VERSION 5.7 ;
  NOWIREEXTENSIONATPIN ON ;
  DIVIDERCHAR "/" ;
  BUSBITCHARS "[]" ;
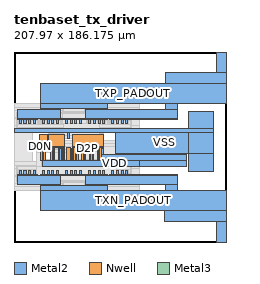
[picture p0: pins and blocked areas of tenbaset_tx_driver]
MACRO tenbaset_tx_driver
  CLASS BLOCK ;
  FOREIGN tenbaset_tx_driver ;
  ORIGIN 0.000 0.000 ;
  SIZE 207.970 BY 186.175 ;
  PIN VSS
    USE GROUND ;
    PORT
      LAYER Metal2 ;
        RECT 170.640 111.690 195.640 128.095 ;
        RECT 0.000 107.460 195.640 111.690 ;
        RECT 52.120 101.325 54.100 107.460 ;
        RECT 99.055 86.690 195.640 107.460 ;
        RECT 170.640 69.305 195.640 86.690 ;
        RECT 170.640 69.305 195.640 128.095 ;
    END
  END VSS
  PIN VDD
    USE POWER ;
    PORT
      LAYER Nwell ;
        RECT 24.710 92.110 32.350 104.990 ;
        RECT 34.050 92.110 49.330 104.990 ;
        RECT 26.450 79.410 30.610 92.110 ;
        RECT 35.790 79.410 39.950 92.110 ;
        RECT 43.430 79.410 47.590 92.110 ;
        RECT 51.030 79.410 55.190 92.290 ;
        RECT 56.890 92.110 87.450 104.990 ;
        RECT 58.630 79.410 62.790 92.110 ;
        RECT 66.270 79.410 70.430 92.110 ;
        RECT 73.910 79.410 78.070 92.110 ;
        RECT 81.550 79.410 85.710 92.110 ;
      LAYER Metal2 ;
        RECT 27.980 79.870 29.080 91.490 ;
        RECT 37.320 79.870 38.420 91.490 ;
        RECT 44.960 79.870 46.060 91.490 ;
        RECT 48.430 79.870 49.860 91.695 ;
        RECT 56.350 79.870 57.780 91.695 ;
        RECT 60.160 79.870 61.260 91.490 ;
        RECT 67.800 79.870 68.900 91.490 ;
        RECT 75.440 79.870 76.540 91.490 ;
        RECT 83.080 79.870 84.180 91.490 ;
        RECT 85.860 86.225 87.290 91.395 ;
        RECT 85.860 79.870 168.970 86.225 ;
        RECT 27.980 74.125 168.970 79.870 ;
        RECT 123.24 74.125 168.970 86.225 ;
    END
  END VDD
  PIN TXP_PADOUT
    ANTENNADIFFAREA 148.000000 ;
    PORT
      LAYER Metal2 ;
        RECT 197.970 165.675 207.970 186.175 ;
        RECT 147.970 155.675 207.970 165.675 ;
        RECT 25.940 135.675 207.970 155.675 ;
        RECT 25.940 130.975 91.300 135.675 ;
        RECT 25.940 130.280 45.960 130.975 ;
        RECT 3.270 121.280 45.960 130.280 ;
        RECT 70.370 130.280 91.300 130.975 ;
        RECT 147.970 130.280 160.685 135.675 ;
        RECT 70.370 121.280 160.685 130.280 ;
        RECT 3.270 119.750 23.290 121.280 ;
        RECT 25.940 119.750 91.300 121.280 ;
        RECT 93.950 119.750 160.685 121.280 ;
        RECT 5.180 115.710 7.180 119.750 ;
        RECT 9.780 115.710 11.780 119.750 ;
        RECT 14.385 115.710 16.385 119.750 ;
        RECT 18.990 115.710 20.990 119.750 ;
        RECT 27.850 115.710 29.850 119.750 ;
        RECT 32.450 115.710 34.450 119.750 ;
        RECT 37.055 115.710 39.055 119.750 ;
        RECT 41.660 115.710 43.660 119.750 ;
        RECT 50.520 115.710 52.520 119.750 ;
        RECT 55.120 115.710 57.120 119.750 ;
        RECT 59.725 115.710 61.725 119.750 ;
        RECT 64.330 115.710 66.330 119.750 ;
        RECT 73.190 115.710 75.190 119.750 ;
        RECT 77.790 115.710 79.790 119.750 ;
        RECT 82.395 115.710 84.395 119.750 ;
        RECT 87.000 115.710 89.000 119.750 ;
        RECT 95.860 115.710 97.860 119.750 ;
        RECT 100.460 115.710 102.460 119.750 ;
        RECT 105.065 115.710 107.065 119.750 ;
        RECT 109.670 115.710 111.670 119.750 ;
    END
  END TXP_PADOUT
  PIN TXN_PADOUT
    ANTENNADIFFAREA 148.000000 ;
    PORT
      LAYER Metal2 ;
        RECT 5.180 66.425 7.180 70.465 ;
        RECT 9.780 66.425 11.780 70.465 ;
        RECT 14.385 66.425 16.385 70.465 ;
        RECT 18.990 66.425 20.990 70.465 ;
        RECT 27.850 66.425 29.850 70.465 ;
        RECT 32.450 66.425 34.450 70.465 ;
        RECT 37.055 66.425 39.055 70.465 ;
        RECT 41.660 66.425 43.660 70.465 ;
        RECT 50.520 66.425 52.520 70.465 ;
        RECT 55.120 66.425 57.120 70.465 ;
        RECT 59.725 66.425 61.725 70.465 ;
        RECT 64.330 66.425 66.330 70.465 ;
        RECT 73.190 66.425 75.190 70.465 ;
        RECT 77.790 66.425 79.790 70.465 ;
        RECT 82.395 66.425 84.395 70.465 ;
        RECT 87.000 66.425 89.000 70.465 ;
        RECT 95.860 66.425 97.860 70.465 ;
        RECT 100.460 66.425 102.460 70.465 ;
        RECT 105.065 66.425 107.065 70.465 ;
        RECT 109.670 66.425 111.670 70.465 ;
        RECT 3.270 64.895 23.290 66.425 ;
        RECT 25.940 64.895 91.300 66.425 ;
        RECT 93.950 64.895 160.685 66.425 ;
        RECT 3.270 55.895 45.960 64.895 ;
        RECT 25.940 55.200 45.960 55.895 ;
        RECT 70.370 55.895 160.685 64.895 ;
        RECT 70.370 55.200 91.300 55.895 ;
        RECT 25.940 50.500 91.300 55.200 ;
        RECT 147.970 50.500 160.685 55.895 ;
        RECT 25.940 30.500 207.970 50.500 ;
        RECT 147.910 20.500 207.970 30.500 ;
        RECT 197.970 0.000 207.970 20.500 ;
    END
  END TXN_PADOUT
  PIN D0N
    ANTENNAGATEAREA 10.000000 ;
    PORT
      LAYER Metal2 ;
        RECT 25.460 92.930 25.960 93.250 ;
    END
  END D0N
  PIN D0P
    ANTENNAGATEAREA 10.000000 ;
    PORT
      LAYER Metal2 ;
        RECT 31.100 92.930 31.600 93.250 ;
    END
  END D0P
  PIN D1P
    ANTENNAGATEAREA 20.000000 ;
    PORT
      LAYER Metal2 ;
        RECT 40.440 92.930 42.940 93.250 ;
    END
  END D1P
  PIN D1N
    ANTENNAGATEAREA 20.000000 ;
    PORT
      LAYER Metal3 ;
        RECT 34.800 92.930 48.580 93.250 ;
    END
  END D1N
  PIN D2N
    ANTENNAGATEAREA 40.000000 ;
    PORT
      LAYER Metal3 ;
        RECT 57.640 92.930 86.700 93.250 ;
    END
  END D2N
  PIN D2P
    ANTENNAGATEAREA 40.000000 ;
    PORT
      LAYER Metal3 ;
        RECT 64.365 91.745 79.975 92.195 ;
    END
  END D2P
  OBS
      LAYER Metal1 ;
        RECT 0.000 131.565 123.240 135.565 ;
        RECT 0.000 129.145 47.340 131.565 ;
        RECT 48.605 129.405 68.630 130.675 ;
        RECT 69.900 129.145 123.240 131.565 ;
        RECT 0.000 128.785 123.240 129.145 ;
        RECT 0.000 122.105 47.700 128.785 ;
        RECT 48.610 128.055 68.630 128.435 ;
        RECT 48.000 127.315 48.380 127.985 ;
        RECT 48.000 126.935 68.630 127.315 ;
        RECT 48.000 125.075 48.380 126.935 ;
        RECT 48.610 125.815 68.630 126.195 ;
        RECT 48.000 124.695 68.630 125.075 ;
        RECT 48.000 122.905 48.380 124.695 ;
        RECT 48.610 123.575 68.630 123.955 ;
        RECT 48.000 122.835 48.610 122.905 ;
        RECT 48.000 122.455 68.630 122.835 ;
        RECT 69.540 122.105 123.240 128.785 ;
        RECT 0.000 120.920 123.240 122.105 ;
        RECT 0.000 114.240 2.360 120.920 ;
        RECT 3.270 120.190 23.290 120.570 ;
        RECT 2.660 115.040 3.040 120.120 ;
        RECT 3.270 119.070 23.290 119.450 ;
        RECT 3.270 117.950 23.290 118.330 ;
        RECT 3.270 116.830 23.290 117.210 ;
        RECT 3.270 115.710 23.290 116.090 ;
        RECT 3.270 114.590 23.290 114.970 ;
        RECT 24.200 114.240 25.030 120.920 ;
        RECT 25.940 120.190 45.960 120.570 ;
        RECT 25.330 115.040 25.710 120.120 ;
        RECT 25.940 119.070 45.960 119.450 ;
        RECT 25.940 117.950 45.960 118.330 ;
        RECT 25.940 116.830 45.960 117.210 ;
        RECT 25.940 115.710 45.960 116.090 ;
        RECT 25.940 114.590 45.960 114.970 ;
        RECT 46.870 114.240 47.700 120.920 ;
        RECT 48.610 120.190 68.630 120.570 ;
        RECT 48.000 115.040 48.380 120.120 ;
        RECT 48.610 119.070 68.630 119.450 ;
        RECT 48.610 117.950 68.630 118.330 ;
        RECT 48.610 116.830 68.630 117.210 ;
        RECT 48.610 115.710 68.630 116.090 ;
        RECT 48.610 114.590 68.630 114.970 ;
        RECT 69.540 114.240 70.370 120.920 ;
        RECT 71.280 120.190 91.300 120.570 ;
        RECT 70.670 115.040 71.050 120.120 ;
        RECT 71.280 119.070 91.300 119.450 ;
        RECT 71.280 117.950 91.300 118.330 ;
        RECT 71.280 116.830 91.300 117.210 ;
        RECT 71.280 115.710 91.300 116.090 ;
        RECT 71.280 114.590 91.300 114.970 ;
        RECT 92.210 114.240 93.040 120.920 ;
        RECT 93.950 120.190 113.970 120.570 ;
        RECT 93.340 115.040 93.720 120.120 ;
        RECT 93.950 119.070 113.970 119.450 ;
        RECT 93.950 117.950 113.970 118.330 ;
        RECT 93.950 116.830 113.970 117.210 ;
        RECT 93.950 115.710 113.970 116.090 ;
        RECT 93.950 114.590 113.970 114.970 ;
        RECT 114.880 114.240 123.240 120.920 ;
        RECT 0.000 113.880 123.240 114.240 ;
        RECT 0.000 111.690 2.000 113.880 ;
        RECT 3.265 112.350 23.290 113.620 ;
        RECT 24.200 111.690 25.030 113.880 ;
        RECT 25.935 112.350 45.960 113.620 ;
        RECT 46.870 111.690 47.700 113.880 ;
        RECT 48.605 112.350 68.630 113.620 ;
        RECT 69.540 111.690 70.370 113.880 ;
        RECT 71.275 112.350 91.300 113.620 ;
        RECT 92.210 111.690 93.040 113.880 ;
        RECT 93.945 112.350 113.970 113.620 ;
        RECT 115.240 111.690 123.240 113.880 ;
        RECT 0.000 107.460 123.240 111.690 ;
        RECT 0.000 78.715 18.355 107.460 ;
        RECT 24.870 104.470 49.170 104.830 ;
        RECT 24.870 92.630 25.230 104.470 ;
        RECT 25.580 93.540 25.960 103.560 ;
        RECT 26.600 93.540 26.980 103.560 ;
        RECT 27.620 93.540 28.000 103.560 ;
        RECT 25.460 92.930 27.550 93.250 ;
        RECT 28.350 92.630 28.710 104.470 ;
        RECT 29.060 93.540 29.440 103.560 ;
        RECT 30.080 93.540 30.460 103.560 ;
        RECT 31.100 93.540 31.480 103.560 ;
        RECT 29.510 92.930 31.600 93.250 ;
        RECT 31.830 92.630 34.570 104.470 ;
        RECT 34.920 93.540 35.300 103.560 ;
        RECT 35.940 93.540 36.320 103.560 ;
        RECT 36.960 93.540 37.340 103.560 ;
        RECT 34.800 92.930 36.890 93.250 ;
        RECT 37.690 92.630 38.050 104.470 ;
        RECT 38.400 93.540 38.780 103.560 ;
        RECT 39.420 93.540 39.800 103.560 ;
        RECT 40.440 93.540 40.820 103.560 ;
        RECT 38.850 92.930 40.940 93.250 ;
        RECT 41.170 92.630 42.210 104.470 ;
        RECT 42.560 93.540 42.940 103.560 ;
        RECT 43.580 93.540 43.960 103.560 ;
        RECT 44.600 93.540 44.980 103.560 ;
        RECT 42.440 92.930 44.530 93.250 ;
        RECT 45.330 92.630 45.690 104.470 ;
        RECT 46.040 93.540 46.420 103.560 ;
        RECT 47.060 93.540 47.440 103.560 ;
        RECT 48.080 93.540 48.460 103.560 ;
        RECT 46.490 92.930 48.580 93.250 ;
        RECT 48.810 92.630 49.170 104.470 ;
        RECT 52.110 104.295 54.070 107.460 ;
        RECT 57.050 104.470 87.290 104.830 ;
        RECT 52.110 103.935 54.110 104.295 ;
        RECT 52.110 103.065 54.100 103.935 ;
        RECT 52.120 101.325 54.100 103.065 ;
        RECT 24.870 92.270 49.170 92.630 ;
        RECT 52.120 92.360 54.100 94.405 ;
        RECT 57.050 92.630 57.410 104.470 ;
        RECT 57.760 93.540 58.140 103.560 ;
        RECT 58.780 93.540 59.160 103.560 ;
        RECT 59.800 93.540 60.180 103.560 ;
        RECT 57.640 92.930 59.730 93.250 ;
        RECT 60.530 92.630 60.890 104.470 ;
        RECT 61.240 93.540 61.620 103.560 ;
        RECT 62.260 93.540 62.640 103.560 ;
        RECT 63.280 93.540 63.660 103.560 ;
        RECT 61.690 92.930 63.780 93.250 ;
        RECT 64.010 92.630 65.050 104.470 ;
        RECT 65.400 93.540 65.780 103.560 ;
        RECT 66.420 93.540 66.800 103.560 ;
        RECT 67.440 93.540 67.820 103.560 ;
        RECT 65.280 92.930 67.370 93.250 ;
        RECT 68.170 92.630 68.530 104.470 ;
        RECT 68.880 93.540 69.260 103.560 ;
        RECT 69.900 93.540 70.280 103.560 ;
        RECT 70.920 93.540 71.300 103.560 ;
        RECT 69.330 92.930 71.420 93.250 ;
        RECT 71.650 92.630 72.690 104.470 ;
        RECT 73.040 93.540 73.420 103.560 ;
        RECT 74.060 93.540 74.440 103.560 ;
        RECT 75.080 93.540 75.460 103.560 ;
        RECT 72.920 92.930 75.010 93.250 ;
        RECT 75.810 92.630 76.170 104.470 ;
        RECT 76.520 93.540 76.900 103.560 ;
        RECT 77.540 93.540 77.920 103.560 ;
        RECT 78.560 93.540 78.940 103.560 ;
        RECT 76.970 92.930 79.060 93.250 ;
        RECT 79.290 92.630 80.330 104.470 ;
        RECT 80.680 93.540 81.060 103.560 ;
        RECT 81.700 93.540 82.080 103.560 ;
        RECT 82.720 93.540 83.100 103.560 ;
        RECT 80.560 92.930 82.650 93.250 ;
        RECT 83.450 92.630 83.810 104.470 ;
        RECT 84.160 93.540 84.540 103.560 ;
        RECT 85.180 93.540 85.560 103.560 ;
        RECT 86.200 93.540 86.580 103.560 ;
        RECT 84.610 92.930 86.700 93.250 ;
        RECT 86.930 92.630 87.290 104.470 ;
        RECT 57.050 92.270 87.290 92.630 ;
        RECT 26.610 91.090 30.450 92.270 ;
        RECT 26.610 79.930 26.970 91.090 ;
        RECT 27.320 80.840 27.700 90.860 ;
        RECT 28.340 80.840 28.720 91.090 ;
        RECT 29.360 80.840 29.740 90.860 ;
        RECT 27.200 80.230 29.290 80.590 ;
        RECT 30.090 79.930 30.450 91.090 ;
        RECT 26.610 79.570 30.450 79.930 ;
        RECT 35.950 92.130 51.190 92.270 ;
        RECT 55.030 92.130 87.290 92.270 ;
        RECT 35.950 91.770 87.290 92.130 ;
        RECT 35.950 91.090 51.550 91.770 ;
        RECT 35.950 79.930 36.310 91.090 ;
        RECT 36.660 80.840 37.040 90.860 ;
        RECT 37.680 80.840 38.060 91.090 ;
        RECT 38.700 80.840 39.080 90.860 ;
        RECT 36.540 80.230 38.630 80.590 ;
        RECT 39.430 79.930 39.790 91.090 ;
        RECT 35.950 79.570 39.790 79.930 ;
        RECT 43.590 79.930 43.950 91.090 ;
        RECT 44.300 80.840 44.680 90.860 ;
        RECT 45.320 80.840 45.700 91.090 ;
        RECT 47.070 90.860 51.550 91.090 ;
        RECT 46.340 80.840 46.720 90.860 ;
        RECT 47.070 80.840 52.280 90.860 ;
        RECT 44.750 80.230 46.840 80.590 ;
        RECT 47.070 79.930 51.550 80.840 ;
        RECT 52.540 80.550 53.680 91.470 ;
        RECT 54.670 91.090 87.290 91.770 ;
        RECT 54.670 90.860 59.150 91.090 ;
        RECT 53.940 80.840 59.150 90.860 ;
        RECT 59.500 80.840 59.880 90.860 ;
        RECT 60.520 80.840 60.900 91.090 ;
        RECT 61.540 80.840 61.920 90.860 ;
        RECT 52.350 80.230 53.870 80.550 ;
        RECT 54.670 79.930 59.150 80.840 ;
        RECT 59.380 80.230 61.470 80.590 ;
        RECT 62.270 79.930 62.630 91.090 ;
        RECT 43.590 79.570 62.630 79.930 ;
        RECT 66.430 79.930 66.790 91.090 ;
        RECT 67.140 80.840 67.520 90.860 ;
        RECT 68.160 80.840 68.540 91.090 ;
        RECT 69.180 80.840 69.560 90.860 ;
        RECT 67.590 80.230 69.680 80.590 ;
        RECT 69.910 79.930 70.270 91.090 ;
        RECT 66.430 79.570 70.270 79.930 ;
        RECT 74.070 79.930 74.430 91.090 ;
        RECT 74.780 80.840 75.160 90.860 ;
        RECT 75.800 80.840 76.180 91.090 ;
        RECT 76.820 80.840 77.200 90.860 ;
        RECT 74.660 80.230 76.750 80.590 ;
        RECT 77.550 79.930 77.910 91.090 ;
        RECT 74.070 79.570 77.910 79.930 ;
        RECT 81.710 79.930 82.070 91.090 ;
        RECT 82.420 80.840 82.800 90.860 ;
        RECT 83.440 80.840 83.820 91.090 ;
        RECT 84.460 80.840 84.840 90.860 ;
        RECT 82.870 80.230 84.960 80.590 ;
        RECT 85.190 79.930 87.290 91.090 ;
        RECT 81.710 79.570 87.290 79.930 ;
        RECT 99.055 78.715 123.240 107.460 ;
        RECT 0.000 74.485 123.240 78.715 ;
        RECT 0.000 72.295 2.000 74.485 ;
        RECT 3.265 72.555 23.290 73.825 ;
        RECT 24.200 72.295 25.030 74.485 ;
        RECT 25.935 72.555 45.960 73.825 ;
        RECT 46.870 72.295 47.700 74.485 ;
        RECT 48.605 72.555 68.630 73.825 ;
        RECT 69.540 72.295 70.370 74.485 ;
        RECT 71.275 72.555 91.300 73.825 ;
        RECT 92.210 72.295 93.040 74.485 ;
        RECT 93.945 72.555 113.970 73.825 ;
        RECT 115.240 72.295 123.240 74.485 ;
        RECT 0.000 71.935 123.240 72.295 ;
        RECT 0.000 65.255 2.360 71.935 ;
        RECT 3.270 71.205 23.290 71.585 ;
        RECT 2.660 66.055 3.040 71.135 ;
        RECT 3.270 70.085 23.290 70.465 ;
        RECT 3.270 68.965 23.290 69.345 ;
        RECT 3.270 67.845 23.290 68.225 ;
        RECT 3.270 66.725 23.290 67.105 ;
        RECT 3.270 65.605 23.290 65.985 ;
        RECT 24.200 65.255 25.030 71.935 ;
        RECT 25.940 71.205 45.960 71.585 ;
        RECT 25.330 66.055 25.710 71.135 ;
        RECT 25.940 70.085 45.960 70.465 ;
        RECT 25.940 68.965 45.960 69.345 ;
        RECT 25.940 67.845 45.960 68.225 ;
        RECT 25.940 66.725 45.960 67.105 ;
        RECT 25.940 65.605 45.960 65.985 ;
        RECT 46.870 65.255 47.700 71.935 ;
        RECT 48.610 71.205 68.630 71.585 ;
        RECT 48.000 66.055 48.380 71.135 ;
        RECT 48.610 70.085 68.630 70.465 ;
        RECT 48.610 68.965 68.630 69.345 ;
        RECT 48.610 67.845 68.630 68.225 ;
        RECT 48.610 66.725 68.630 67.105 ;
        RECT 48.610 65.605 68.630 65.985 ;
        RECT 69.540 65.255 70.370 71.935 ;
        RECT 71.280 71.205 91.300 71.585 ;
        RECT 70.670 66.055 71.050 71.135 ;
        RECT 71.280 70.085 91.300 70.465 ;
        RECT 71.280 68.965 91.300 69.345 ;
        RECT 71.280 67.845 91.300 68.225 ;
        RECT 71.280 66.725 91.300 67.105 ;
        RECT 71.280 65.605 91.300 65.985 ;
        RECT 92.210 65.255 93.040 71.935 ;
        RECT 93.950 71.205 113.970 71.585 ;
        RECT 93.340 66.055 93.720 71.135 ;
        RECT 93.950 70.085 113.970 70.465 ;
        RECT 93.950 68.965 113.970 69.345 ;
        RECT 93.950 67.845 113.970 68.225 ;
        RECT 93.950 66.725 113.970 67.105 ;
        RECT 93.950 65.605 113.970 65.985 ;
        RECT 114.880 65.255 123.240 71.935 ;
        RECT 0.000 64.070 123.240 65.255 ;
        RECT 0.000 57.390 47.700 64.070 ;
        RECT 48.000 63.340 68.630 63.720 ;
        RECT 48.000 63.270 48.610 63.340 ;
        RECT 48.000 61.480 48.380 63.270 ;
        RECT 48.610 62.220 68.630 62.600 ;
        RECT 48.000 61.100 68.630 61.480 ;
        RECT 48.000 59.240 48.380 61.100 ;
        RECT 48.610 59.980 68.630 60.360 ;
        RECT 48.000 58.860 68.630 59.240 ;
        RECT 48.000 58.190 48.380 58.860 ;
        RECT 48.610 57.740 68.630 58.120 ;
        RECT 69.540 57.390 123.240 64.070 ;
        RECT 0.000 57.030 123.240 57.390 ;
        RECT 0.000 54.610 47.340 57.030 ;
        RECT 48.605 55.500 68.630 56.770 ;
        RECT 69.900 54.610 123.240 57.030 ;
        RECT 0.000 50.610 123.240 54.610 ;
      LAYER Metal2 ;
        RECT 48.605 127.615 68.630 130.675 ;
        RECT 48.000 123.575 48.380 127.315 ;
        RECT 50.520 123.275 52.520 127.315 ;
        RECT 52.820 123.575 54.820 127.615 ;
        RECT 55.120 123.275 57.120 127.315 ;
        RECT 57.420 123.575 59.420 127.615 ;
        RECT 59.725 123.275 61.725 127.315 ;
        RECT 62.025 123.575 64.025 127.615 ;
        RECT 64.330 123.275 66.330 127.315 ;
        RECT 66.630 123.575 68.630 127.615 ;
        RECT 48.610 121.745 68.630 123.275 ;
        RECT 2.660 116.085 3.040 119.440 ;
        RECT 7.480 115.410 9.480 119.450 ;
        RECT 12.080 115.410 14.080 119.450 ;
        RECT 16.685 115.410 18.685 119.450 ;
        RECT 21.290 115.410 23.290 119.450 ;
        RECT 25.330 116.085 25.710 119.440 ;
        RECT 30.150 115.410 32.150 119.450 ;
        RECT 34.750 115.410 36.750 119.450 ;
        RECT 39.355 115.410 41.355 119.450 ;
        RECT 43.960 115.410 45.960 119.450 ;
        RECT 48.000 116.090 48.380 119.445 ;
        RECT 52.820 115.410 54.820 119.450 ;
        RECT 57.420 115.410 59.420 119.450 ;
        RECT 62.025 115.410 64.025 119.450 ;
        RECT 66.630 115.410 68.630 119.450 ;
        RECT 70.670 116.090 71.050 119.445 ;
        RECT 75.490 115.410 77.490 119.450 ;
        RECT 80.090 115.410 82.090 119.450 ;
        RECT 84.695 115.410 86.695 119.450 ;
        RECT 89.300 115.410 91.300 119.450 ;
        RECT 93.340 116.090 93.720 119.445 ;
        RECT 98.160 115.410 100.160 119.450 ;
        RECT 102.760 115.410 104.760 119.450 ;
        RECT 107.365 115.410 109.365 119.450 ;
        RECT 111.970 115.410 113.970 119.450 ;
        RECT 3.265 112.355 113.970 115.410 ;
        RECT 3.265 112.350 23.290 112.355 ;
        RECT 25.935 112.350 45.960 112.355 ;
        RECT 48.605 112.350 68.630 112.355 ;
        RECT 71.275 112.350 91.300 112.355 ;
        RECT 93.945 112.350 113.970 112.355 ;
        RECT 34.205 105.110 49.170 106.605 ;
        RECT 34.205 104.830 37.690 105.110 ;
        RECT 24.870 103.840 28.350 104.830 ;
        RECT 24.870 93.540 25.960 103.840 ;
        RECT 26.240 92.630 27.340 103.560 ;
        RECT 27.620 93.540 28.350 103.840 ;
        RECT 28.710 103.840 32.190 104.830 ;
        RECT 28.710 93.540 29.440 103.840 ;
        RECT 29.720 92.630 30.820 103.560 ;
        RECT 31.100 93.540 32.190 103.840 ;
        RECT 34.210 103.840 37.690 104.830 ;
        RECT 34.210 93.540 35.300 103.840 ;
        RECT 34.800 92.930 35.300 93.250 ;
        RECT 26.240 91.770 30.820 92.630 ;
        RECT 35.580 92.630 36.680 103.560 ;
        RECT 36.960 93.540 37.690 103.840 ;
        RECT 38.050 103.840 45.330 104.830 ;
        RECT 38.050 93.540 38.780 103.840 ;
        RECT 39.060 92.630 40.160 103.560 ;
        RECT 40.440 93.540 42.940 103.840 ;
        RECT 35.580 91.770 40.160 92.630 ;
        RECT 43.220 92.630 44.320 103.560 ;
        RECT 44.600 93.540 45.330 103.840 ;
        RECT 45.690 103.840 49.170 105.110 ;
        RECT 57.045 105.110 87.290 106.605 ;
        RECT 57.045 104.830 60.530 105.110 ;
        RECT 45.690 93.540 46.420 103.840 ;
        RECT 46.700 92.630 47.800 103.560 ;
        RECT 48.080 93.540 49.170 103.840 ;
        RECT 57.050 103.840 60.530 104.830 ;
        RECT 48.080 92.930 48.580 93.250 ;
        RECT 43.220 91.770 47.800 92.630 ;
        RECT 26.600 80.840 27.700 91.770 ;
        RECT 29.360 80.840 30.460 91.770 ;
        RECT 35.940 80.840 37.040 91.770 ;
        RECT 38.700 88.950 39.800 91.770 ;
        RECT 43.580 88.950 44.680 91.770 ;
        RECT 38.700 80.840 44.680 88.950 ;
        RECT 46.340 80.840 47.440 91.770 ;
        RECT 27.230 80.200 27.700 80.560 ;
        RECT 36.570 80.200 37.040 80.560 ;
        RECT 46.340 80.200 46.810 80.560 ;
        RECT 52.120 80.225 54.100 94.405 ;
        RECT 57.050 93.540 58.140 103.840 ;
        RECT 57.640 92.930 58.140 93.250 ;
        RECT 58.420 92.630 59.520 103.560 ;
        RECT 59.800 93.540 60.530 103.840 ;
        RECT 60.890 103.840 68.170 104.830 ;
        RECT 60.890 93.540 61.620 103.840 ;
        RECT 61.900 92.630 63.000 103.560 ;
        RECT 63.280 93.540 65.780 103.840 ;
        RECT 63.280 92.930 65.780 93.250 ;
        RECT 58.420 91.770 63.000 92.630 ;
        RECT 58.780 80.840 59.880 91.770 ;
        RECT 61.540 88.950 62.640 91.770 ;
        RECT 64.365 91.745 64.695 92.930 ;
        RECT 66.060 92.630 67.160 103.560 ;
        RECT 67.440 93.540 68.170 103.840 ;
        RECT 68.530 103.840 75.810 105.110 ;
        RECT 68.530 93.540 69.260 103.840 ;
        RECT 69.540 92.630 70.640 103.560 ;
        RECT 70.920 93.540 73.420 103.840 ;
        RECT 70.920 92.930 71.420 93.250 ;
        RECT 72.920 92.930 73.420 93.250 ;
        RECT 66.060 91.770 70.640 92.630 ;
        RECT 73.700 92.630 74.800 103.560 ;
        RECT 75.080 93.540 75.810 103.840 ;
        RECT 76.170 103.840 83.450 104.830 ;
        RECT 76.170 93.540 76.900 103.840 ;
        RECT 77.180 92.630 78.280 103.560 ;
        RECT 78.560 93.540 81.060 103.840 ;
        RECT 78.560 92.930 81.060 93.250 ;
        RECT 73.700 91.770 78.280 92.630 ;
        RECT 66.420 88.950 67.520 91.770 ;
        RECT 61.540 80.840 67.520 88.950 ;
        RECT 69.180 88.950 70.280 91.770 ;
        RECT 74.060 88.950 75.160 91.770 ;
        RECT 69.180 80.840 75.160 88.950 ;
        RECT 76.820 88.950 77.920 91.770 ;
        RECT 79.645 91.745 79.975 92.930 ;
        RECT 81.340 92.630 82.440 103.560 ;
        RECT 82.720 93.540 83.450 103.840 ;
        RECT 83.810 103.840 87.290 105.110 ;
        RECT 83.810 93.540 84.540 103.840 ;
        RECT 84.820 92.630 85.920 103.560 ;
        RECT 86.200 93.540 87.290 103.840 ;
        RECT 86.200 92.930 86.700 93.250 ;
        RECT 81.340 91.770 85.920 92.630 ;
        RECT 81.700 88.950 82.800 91.770 ;
        RECT 76.820 80.840 82.800 88.950 ;
        RECT 84.460 80.840 85.560 91.770 ;
        RECT 59.410 80.200 59.880 80.560 ;
        RECT 69.180 80.200 69.650 80.560 ;
        RECT 74.690 80.200 75.160 80.560 ;
        RECT 84.460 80.200 84.930 80.560 ;
        RECT 3.265 73.820 23.290 73.825 ;
        RECT 25.935 73.820 45.960 73.825 ;
        RECT 48.605 73.820 68.630 73.825 ;
        RECT 71.275 73.820 91.300 73.825 ;
        RECT 93.945 73.820 113.970 73.825 ;
        RECT 3.265 70.765 113.970 73.820 ;
        RECT 2.660 66.735 3.040 70.090 ;
        RECT 7.480 66.725 9.480 70.765 ;
        RECT 12.080 66.725 14.080 70.765 ;
        RECT 16.685 66.725 18.685 70.765 ;
        RECT 21.290 66.725 23.290 70.765 ;
        RECT 25.330 66.735 25.710 70.090 ;
        RECT 30.150 66.725 32.150 70.765 ;
        RECT 34.750 66.725 36.750 70.765 ;
        RECT 39.355 66.725 41.355 70.765 ;
        RECT 43.960 66.725 45.960 70.765 ;
        RECT 48.000 66.730 48.380 70.085 ;
        RECT 52.820 66.725 54.820 70.765 ;
        RECT 57.420 66.725 59.420 70.765 ;
        RECT 62.025 66.725 64.025 70.765 ;
        RECT 66.630 66.725 68.630 70.765 ;
        RECT 70.670 66.730 71.050 70.085 ;
        RECT 75.490 66.725 77.490 70.765 ;
        RECT 80.090 66.725 82.090 70.765 ;
        RECT 84.695 66.725 86.695 70.765 ;
        RECT 89.300 66.725 91.300 70.765 ;
        RECT 93.340 66.730 93.720 70.085 ;
        RECT 98.160 66.725 100.160 70.765 ;
        RECT 102.760 66.725 104.760 70.765 ;
        RECT 107.365 66.725 109.365 70.765 ;
        RECT 111.970 66.725 113.970 70.765 ;
        RECT 48.610 62.900 68.630 64.430 ;
        RECT 48.000 58.860 48.380 62.600 ;
        RECT 50.520 58.860 52.520 62.900 ;
        RECT 52.820 58.560 54.820 62.600 ;
        RECT 55.120 58.860 57.120 62.900 ;
        RECT 57.420 58.560 59.420 62.600 ;
        RECT 59.725 58.860 61.725 62.900 ;
        RECT 62.025 58.560 64.025 62.600 ;
        RECT 64.330 58.860 66.330 62.900 ;
        RECT 66.630 58.560 68.630 62.600 ;
        RECT 48.605 55.500 68.630 58.560 ;
      LAYER Metal3 ;
        RECT 2.660 126.215 93.720 127.315 ;
        RECT 2.660 116.085 3.340 126.215 ;
        RECT 25.330 116.090 26.010 126.215 ;
        RECT 47.620 116.090 71.050 126.215 ;
        RECT 93.040 116.090 93.720 126.215 ;
        RECT 48.760 104.830 83.450 116.090 ;
        RECT 28.710 101.830 83.450 104.830 ;
        RECT 24.870 93.240 28.350 96.540 ;
        RECT 28.710 93.540 32.190 101.830 ;
        RECT 32.490 96.840 100.295 99.840 ;
        RECT 32.490 93.540 37.690 96.840 ;
        RECT 38.050 93.540 45.330 96.540 ;
        RECT 45.690 93.540 60.530 96.840 ;
        RECT 60.890 93.540 68.170 96.540 ;
        RECT 68.530 93.540 75.810 96.840 ;
        RECT 76.170 93.540 83.450 96.540 ;
        RECT 83.810 93.540 100.295 96.840 ;
        RECT 32.490 93.240 34.210 93.540 ;
        RECT 21.930 90.210 34.210 93.240 ;
        RECT 49.170 90.210 57.050 93.540 ;
        RECT 21.930 87.630 57.050 90.210 ;
        RECT 21.930 73.825 26.930 87.630 ;
        RECT 52.120 80.560 54.100 83.020 ;
        RECT 27.230 80.200 84.930 80.560 ;
        RECT 87.980 73.825 100.295 93.540 ;
        RECT 2.660 59.960 3.340 70.090 ;
        RECT 21.930 59.960 100.295 73.825 ;
        RECT 2.660 58.860 100.295 59.960 ;
  END
END tenbaset_tx_driver
END LIBRARY

